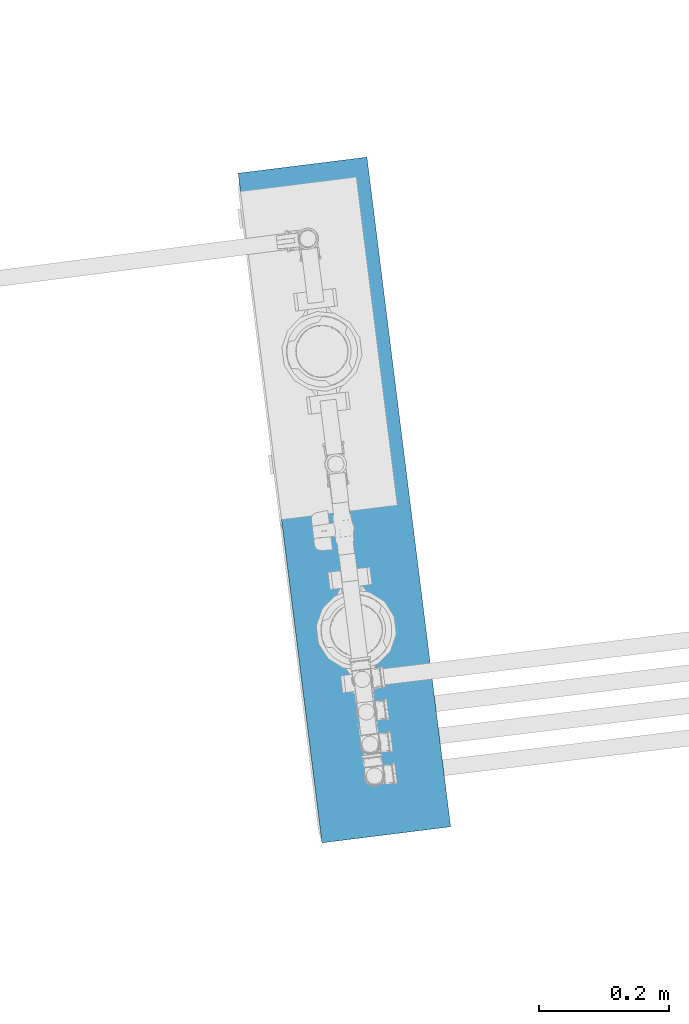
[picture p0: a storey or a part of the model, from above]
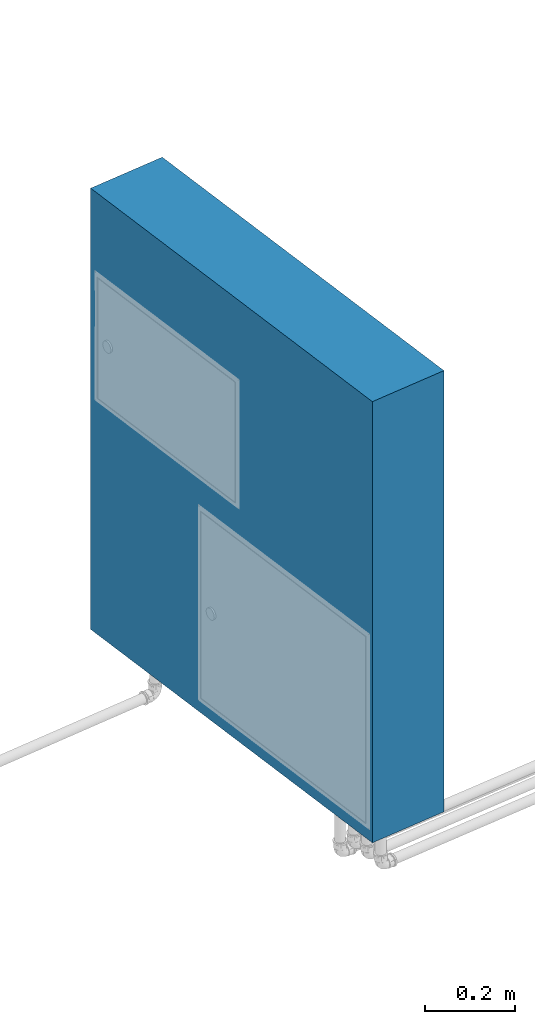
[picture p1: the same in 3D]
Properties of the parts of a building model (IFC2X3), part 1 of 2

# File
Description: ViewDefinition [CoordinationView_V2.0]
Time: 2023-04-20T11:42:16
Written by: The EXPRESS Data Manager Version 5.02.0100.07 : 28 Aug 2013
Made in: 22.0.2.392 - Exporter 22.0.2.392 - IU alternativa 22.0.2.392
Comment: STEP Physical File produced by: The EXPRESS Data Manager Version 5.02.0100.07 : 28 Aug 2013 * Module: EDMstepFileFactory/EDMstandAlone * Creation date: Thu Apr 20 11:42:16 2023 * Host: ESTACAO-11 * Database: D:\bruno.bestetti\AppData\Local\Temp\69208f3e-4a2d-469e-9d8b-66fd437b3669\e22d9549-68a2-4e91-86b9-adf0b3c94b80\ifc * Database version: 5507 * Database creation date: Thu Apr 20 11:41:43 2023 * Schema: IFC2X3 * Model: DataRepository.ifc * Model creation date: Thu Apr 20 11:41:44 2023 * Header model: DataRepository.ifc_HeaderModel * Header model creation date: Thu Apr 20 11:41:44 2023 * EDMuser: sdai-user * EDMgroup: sdai-group * License ID and type: 5605 : Permanent license. Expiry date: * EDMstepFileFactory options: 020000

# IfcProject
LongName: REVITALIZAÇÃO PRAÇA TEÓFILO SCHUTZ; Phase: EXECUTIVO

# IfcSite, Default
RefLatitude: 42, 24, 53, 508911; RefLongitude: -71, -15, -29, -58837; RefElevation: 0 cm

# IfcBuilding, HIDROSSANITÁRIO
LongName: HIDROSSANITÁRIO
Pset_BuildingCommon - NumberOfStoreys: 2

# IfcBuildingStorey: Nível:Nivel Rodrigo MEP (2)
In: HIDROSSANITÁRIO
Name | LongName | Elevation (cm)
TÉRREO-HID | TÉRREO-HID | -260
TERRENO | TERRENO | 0

# IfcBuildingElementProxy: Anel de Concreto para Fossa e Sumidouro_Rodrigo MEP:Anel de Concreto para Fossa e Sumidouro (6)
In: TÉRREO-HID
Type - Material: .CONCRETO
Type - Pset_ManufacturerTypeInformation - Manufacturer: -
Pset_BuildingElementProxyCommon - Reference: Anel de Concreto para Fossa e Sumidouro; sets with these values: 2
Name (Anel de Concreto para Fossa e Sumidouro_Rodrigo MEP:Anel de Concreto para Fossa e Sumidouro:...)
3760591
3761720
3761782
3761790
3761817
3761825

# IfcBuildingElementProxy: Tampa Fossa_Rodrigo MEP:Tampa Fossa (2)
In: TÉRREO-HID
Type - Material: .CONCRETO
Pset_BuildingElementProxyCommon - Reference: Tampa Fossa; sets with these values: 2
Name (Tampa Fossa_Rodrigo MEP:Tampa Fossa:...)
3757781
3757826

# IfcDistributionPort (947)
Description: Flow
Name | FlowDirection | Group
InPort_3621336 | SINK | Água Fria 1
2 x OutPort_3631671 | SOURCE | Água Fria 1
InPort_3621421 | SINK | Água Fria 1
OutPort_3621336 | SOURCE | Água Fria 1
InPort_3621553 | SINK | Água Fria 1
OutPort_3621421 | SOURCE | Água Fria 1
InPort_3622171 | SINK | Água Fria 1
OutPort_3622167 | SOURCE | Água Fria 1
InPort_3622167 | SINK | Água Fria 1
OutPort_3622169 | SOURCE | Água Fria 1
InPort_3622169 | SINK | Água Fria 1
OutPort_3622227 | SOURCE | Água Fria 1
InPort_3622173 | SINK | Água Fria 1
OutPort_3622171 | SOURCE | Água Fria 1
InPort_3622227 | SINK | Água Fria 1
Port_3622611 | SOURCEANDSINK | Esgoto Primário 1
InPort_3622611 | SOURCEANDSINK | Esgoto Primário 1
2 x OutPort_3706232 | SOURCEANDSINK | Esgoto Primário 1
2 x InPort_3622626 | SOURCEANDSINK | Esgoto Primário 1
OutPort_3647421 | SOURCEANDSINK | Esgoto Primário 1
InPort_3623081 | SOURCEANDSINK | Esgoto Primário 1
2 x OutPort_3623085 | SOURCEANDSINK | Esgoto Primário 1
Port_3623081 | SOURCEANDSINK | Esgoto Primário 1
2 x InPort_3623083 | SOURCEANDSINK | Esgoto Primário 1
OutPort_3623249 | SOURCEANDSINK | Esgoto Primário 1
2 x Port_3623087 | SOURCEANDSINK
InPort_3623102 | SOURCEANDSINK | Esgoto Primário 1
2 x OutPort_3623106 | SOURCEANDSINK | Esgoto Primário 1
Port_3623102 | SOURCEANDSINK | Esgoto Primário 1
2 x InPort_3623104 | SOURCEANDSINK | Esgoto Primário 1
OutPort_3623216 | SOURCEANDSINK | Esgoto Primário 1
2 x Port_3623108 | SOURCEANDSINK
InPort_3623121 | SOURCEANDSINK | Esgoto Primário 1
2 x OutPort_3623125 | SOURCEANDSINK | Esgoto Primário 1
Port_3623121 | SOURCEANDSINK | Esgoto Primário 1
2 x InPort_3623123 | SOURCEANDSINK | Esgoto Primário 1
OutPort_3623181 | SOURCEANDSINK | Esgoto Primário 1
2 x Port_3623127 | SOURCEANDSINK
2 x InPort_3623181 | SOURCEANDSINK | Esgoto Primário 1
OutPort_3624440 | SOURCEANDSINK | Esgoto Primário 1
2 x OutPort_3705811 | SOURCEANDSINK | Esgoto Primário 1
2 x Port_3623183 | SOURCEANDSINK
2 x InPort_3623216 | SOURCEANDSINK | Esgoto Primário 1
2 x OutPort_3624463 | SOURCEANDSINK | Esgoto Primário 1
2 x OutPort_3731357 | SOURCEANDSINK | Esgoto Primário 1
2 x Port_3623218 | SOURCEANDSINK
2 x InPort_3623249 | SOURCEANDSINK | Esgoto Primário 1
OutPort_3704790 | SOURCEANDSINK | Esgoto Primário 1
OutPort_3632646 | SOURCEANDSINK | Esgoto Primário 1
2 x Port_3623251 | SOURCEANDSINK
6 x Port_3623956 | SOURCE
InPort_3707539 | SINK | Esgoto Primário 1
OutPort_3623956 | SOURCE | Esgoto Primário 1
InPort_3623956 | SINK | Esgoto Primário 2
OutPort_3706054 | SOURCE | Esgoto Primário 2
InPort_3624235 | SINK | Esgoto Primário 1
OutPort_3707566 | SOURCE | Esgoto Primário 1
InPort_3624462 | SINK | Esgoto Primário 1
OutPort_3624235 | SOURCE | Esgoto Primário 1
InPort_3624440 | SOURCEANDSINK | Esgoto Primário 1
OutPort_3624462 | SOURCEANDSINK | Esgoto Primário 1
InPort_3624462 | SOURCEANDSINK | Esgoto Primário 1
2 x Port_3624466 | SOURCEANDSINK
InPort_3625453 | SINK | Esgoto Primário 2
OutPort_3625024 | SOURCE | Esgoto Primário 2
InPort_3625483 | SINK | Esgoto Primário 2
OutPort_3625453 | SOURCE | Esgoto Primário 2
InPort_3635714 | SINK | Esgoto Primário 2
OutPort_3625471 | SOURCE | Esgoto Primário 2
InPort_3625471 | SINK | Esgoto Primário 2
OutPort_3625483 | SOURCE | Esgoto Primário 2
2 x InPort_3635718 | SINK | Esgoto Primário 2
OutPort_3625487 | SOURCE | Esgoto Primário 2
InPort_3625487 | SINK | Esgoto Primário 2
OutPort_3635714 | SOURCE | Esgoto Primário 2
InPort_3625944 | SINK | Esgoto Primário 2
OutPort_3625943 | SOURCE | Esgoto Primário 2
InPort_3625948 | SINK | Esgoto Primário 2
OutPort_3625944 | SOURCE | Esgoto Primário 2
InPort_3625946 | SINK | Esgoto Primário 2
OutPort_3625948 | SOURCE | Esgoto Primário 2
InPort_3625952 | SINK | Esgoto Primário 2
OutPort_3625946 | SOURCE | Esgoto Primário 2
InPort_3625950 | SINK | Esgoto Primário 2
OutPort_3625952 | SOURCE | Esgoto Primário 2
InPort_3635676 | SINK | Esgoto Primário 2
OutPort_3625950 | SOURCE | Esgoto Primário 2
InPort_3628157 | SINK | Água Fria 4
2 x OutPort_3628572 | SOURCE | Água Fria 4
2 x Port_3628157 | SOURCE
2 x Port_3628157 | SINK
InPort_3723032 | SINK | Água Fria 1
2 x OutPort_3628157 | SOURCE | Água Fria 1
InPort_3630028 | SINK | Água Fria 1
InPort_3628157 | SINK | Água Fria 1
OutPort_3723612 | SOURCE | Água Fria 1
Port_3628158 | SOURCE
InPort_3628812 | SINK | Água Fria 4
InPort_3628572 | SINK | Água Fria 4
OutPort_3628157 | SOURCE | Água Fria 4
InPort_3628820 | SINK | Água Fria 4
OutPort_3628802 | SOURCE | Água Fria 4
InPort_3628802 | SINK | Água Fria 4
OutPort_3628812 | SOURCE | Água Fria 4
InPort_3628832 | SINK | Água Fria 4
OutPort_3628814 | SOURCE | Água Fria 4
InPort_3628814 | SINK | Água Fria 4
OutPort_3628820 | SOURCE | Água Fria 4
InPort_3628840 | SINK | Água Fria 4
OutPort_3628824 | SOURCE | Água Fria 4
InPort_3628824 | SINK | Água Fria 4
OutPort_3628832 | SOURCE | Água Fria 4
InPort_3648340 | SINK | Água Fria 4
OutPort_3628840 | SOURCE | Água Fria 4
InPort_3629752 | SINK | Água Fria 1
OutPort_3629689 | SOURCE | Água Fria 1
InPort_3629689 | SINK | Água Fria 1
2 x OutPort_3656299 | SOURCE | Água Fria 1
InPort_3630155 | SINK | Água Fria 1
OutPort_3629752 | SOURCE | Água Fria 1
InPort_3629826 | SINK | Água Fria 1
OutPort_3656307 | SOURCE | Água Fria 1
InPort_3629832 | SINK | Água Fria 1
OutPort_3629826 | SOURCE | Água Fria 1
InPort_3630368 | SINK | Água Fria 1
OutPort_3629832 | SOURCE | Água Fria 1
InPort_3629846 | SINK | Água Fria 1
OutPort_3656433 | SOURCE | Água Fria 1
InPort_3629852 | SINK | Água Fria 1
OutPort_3629846 | SOURCE | Água Fria 1
InPort_3630320 | SINK | Água Fria 1
OutPort_3629852 | SOURCE | Água Fria 1
InPort_3656427 | SINK | Água Fria 1
OutPort_3629868 | SOURCE | Água Fria 1
InPort_3629868 | SINK | Água Fria 1
OutPort_3632177 | SOURCE | Água Fria 1
InPort_3629874 | SINK | Água Fria 1
OutPort_3656428 | SOURCE | Água Fria 1
InPort_3630357 | SINK | Água Fria 1
OutPort_3629874 | SOURCE | Água Fria 1
InPort_3629916 | SINK | Água Fria 1
InPort_3656307 | SINK | Água Fria 1
OutPort_3629916 | SOURCE | Água Fria 1
InPort_3629988 | SINK | Água Fria 1
2 x OutPort_3656427 | SOURCE | Água Fria 1
InPort_3656433 | SINK | Água Fria 1
OutPort_3629988 | SOURCE | Água Fria 1
InPort_3657158 | SINK | Água Fria 1
OutPort_3630028 | SOURCE | Água Fria 1
InPort_3657128 | SINK | Água Fria 1
OutPort_3630072 | SOURCE | Água Fria 1
InPort_3630072 | SINK | Água Fria 1
2 x OutPort_3657158 | SOURCE | Água Fria 1
InPort_3630472 | SINK | Água Fria 1
OutPort_3630470 | SOURCE | Água Fria 1
InPort_3630470 | SINK | Água Fria 1
2 x OutPort_3631200 | SOURCE | Água Fria 1
InPort_3630476 | SINK | Água Fria 1
OutPort_3630472 | SOURCE | Água Fria 1
InPort_3630937 | SINK | Água Fria 1
OutPort_3656827 | SOURCE | Água Fria 1
InPort_3631019 | SINK | Água Fria 1
OutPort_3630937 | SOURCE | Água Fria 1
InPort_3631121 | SINK | Água Fria 1
OutPort_3631019 | SOURCE | Água Fria 1
InPort_3656764 | SINK | Água Fria 1
InPort_3631200 | SINK | Água Fria 1
OutPort_3631201 | SOURCE | Água Fria 1
InPort_3631201 | SINK | Água Fria 1
OutPort_3632300 | SOURCE | Água Fria 1
InPort_3632177 | SINK | Água Fria 1
OutPort_3631272 | SOURCE | Água Fria 1
InPort_3631272 | SINK | Água Fria 1
2 x OutPort_3656704 | SOURCE | Água Fria 1
InPort_3631287 | SINK | Água Fria 1
OutPort_3656568 | SOURCE | Água Fria 1
InPort_3656704 | SINK | Água Fria 1
OutPort_3631287 | SOURCE | Água Fria 1
InPort_3632149 | SINK | Água Fria 1
OutPort_3631337 | SOURCE | Água Fria 1
InPort_3631337 | SINK | Água Fria 1
2 x OutPort_3656640 | SOURCE | Água Fria 1
InPort_3656640 | SINK | Água Fria 1
OutPort_3631352 | SOURCE | Água Fria 1
InPort_3631352 | SINK | Água Fria 1
OutPort_3656571 | SOURCE | Água Fria 1
InPort_3631474 | SINK | Água Fria 1
2 x OutPort_3657128 | SOURCE | Água Fria 1
InPort_3656571 | SINK | Água Fria 1
OutPort_3631474 | SOURCE | Água Fria 1
InPort_3631671 | SINK | Água Fria 1
OutPort_3632028 | SOURCE | Água Fria 1
InPort_3632021 | SINK | Água Fria 1
OutPort_3631682 | SOURCE | Água Fria 1
InPort_3631682 | SINK | Água Fria 1
OutPort_3631703 | SOURCE | Água Fria 1
InPort_3631703 | SINK | Água Fria 1
OutPort_3631697 | SOURCE | Água Fria 1
InPort_3631697 | SINK | Água Fria 1
OutPort_3657137 | SOURCE | Água Fria 1
InPort_3632028 | SINK | Água Fria 1
OutPort_3632021 | SOURCE | Água Fria 1
InPort_3656460 | SINK | Água Fria 1
OutPort_3632149 | SOURCE | Água Fria 1
InPort_3632300 | SINK | Água Fria 1
OutPort_3632330 | SOURCE | Água Fria 1
InPort_3632330 | SINK | Água Fria 1
OutPort_3656670 | SOURCE | Água Fria 1
InPort_3633401 | SINK | Esgoto Primário 3
OutPort_3632400 | SOURCE | Esgoto Primário 3
Port_3632472 | SOURCEANDSINK | Esgoto Primário 1
InPort_3632472 | SOURCEANDSINK | Esgoto Primário 1
2 x OutPort_3705473 | SOURCEANDSINK | Esgoto Primário 1
InPort_3632646 | SOURCEANDSINK | Esgoto Primário 1
OutPort_3731356 | SOURCEANDSINK | Esgoto Primário 1
6 x Port_3633080 | SOURCE
InPort_3707350 | SINK | Esgoto Primário 1
OutPort_3633080 | SOURCE | Esgoto Primário 1
InPort_3633080 | SINK | Esgoto Primário 3
OutPort_3708016 | SOURCE | Esgoto Primário 3
InPort_3655015 | SINK | Esgoto Primário 3
OutPort_3633401 | SOURCE | Esgoto Primário 3
InPort_3633724 | SINK | Esgoto Primário 3
OutPort_3708036 | SOURCE | Esgoto Primário 3
InPort_3708065 | SINK | Esgoto Primário 3
OutPort_3633724 | SOURCE | Esgoto Primário 3
InPort_3708036 | SINK | Esgoto Primário 3
OutPort_3633733 | SOURCE | Esgoto Primário 3
InPort_3633733 | SINK | Esgoto Primário 3
OutPort_3655015 | SOURCE | Esgoto Primário 3
2 x InPort_3633823 | SOURCEANDSINK | Esgoto Primário 1
2 x OutPort_3705804 | SOURCEANDSINK | Esgoto Primário 1
OutPort_3635577 | SOURCE | Esgoto Primário 2
InPort_3635577 | SINK | Esgoto Primário 2
OutPort_3635676 | SOURCE | Esgoto Primário 2
InPort_3706054 | SINK | Esgoto Primário 2
OutPort_3635718 | SOURCE | Esgoto Primário 2
InPort_3637866 | SOURCEANDSINK | Gordura 1
OutPort_3637925 | SOURCEANDSINK | Gordura 1
Port_3637866 | SOURCEANDSINK | Gordura 1
InPort_3637925 | SOURCEANDSINK | Gordura 1
OutPort_3644001 | SOURCEANDSINK | Gordura 1
2 x Port_3637927 | SOURCEANDSINK
Port_3638030 | SOURCEANDSINK | Gordura 2
InPort_3638030 | SOURCEANDSINK | Gordura 2
OutPort_3638036 | SOURCEANDSINK | Gordura 2
InPort_3638036 | SOURCEANDSINK | Gordura 2
OutPort_3644162 | SOURCEANDSINK | Gordura 2
2 x Port_3638038 | SOURCEANDSINK
2 x Port_3638080 | SOURCEANDSINK | Esgoto Primário 7
2 x Port_3638102 | SOURCEANDSINK | Esgoto Primário 8
2 x Port_3638151 | SOURCEANDSINK | Esgoto Primário 9
2 x InPort_3708612 | SINK | Ventilação-ESG 3
OutPort_3638600 | SOURCE | Ventilação-ESG 3
InPort_3638600 | SINK | Ventilação-ESG 3
OutPort_3643844 | SOURCE | Ventilação-ESG 3
Port_3638873 | SOURCEANDSINK | Gordura 3
InPort_3638873 | SOURCEANDSINK | Gordura 3
OutPort_3638879 | SOURCEANDSINK | Gordura 3
InPort_3638879 | SOURCEANDSINK | Gordura 3
OutPort_3644209 | SOURCEANDSINK | Gordura 3
2 x Port_3638881 | SOURCEANDSINK
Port_3643488 | SOURCEANDSINK
InPort_3643999 | SOURCEANDSINK | Gordura 1
2 x OutPort_3644003 | SOURCEANDSINK | Gordura 1
Port_3643999 | SOURCEANDSINK | Gordura 1
InPort_3644001 | SOURCEANDSINK | Gordura 1
2 x Port_3644006 | SOURCEANDSINK
Port_3644160 | SOURCEANDSINK | Gordura 2
InPort_3644160 | SOURCEANDSINK | Gordura 2
2 x OutPort_3644164 | SOURCEANDSINK | Gordura 2
InPort_3644162 | SOURCEANDSINK | Gordura 2
2 x Port_3644166 | SOURCEANDSINK
2 x InPort_3644205 | SOURCEANDSINK | Gordura 3
2 x OutPort_3644211 | SOURCEANDSINK | Gordura 3
2 x OutPort_3644217 | SOURCEANDSINK | Gordura 3
Port_3644207 | SOURCEANDSINK | Gordura 3
InPort_3644207 | SOURCEANDSINK | Gordura 3
InPort_3644209 | SOURCEANDSINK | Gordura 3
2 x Port_3644213 | SOURCEANDSINK
2 x Port_3644220 | SOURCEANDSINK
InPort_3644762 | SINK | Água Fria 3
OutPort_3645447 | SOURCE | Água Fria 3
2 x InPort_3747857 | SINK | Água Fria 3
OutPort_3644762 | SOURCE | Água Fria 3
InPort_3644793 | SINK | Água Fria 3
OutPort_3644799 | SOURCE | Água Fria 3
InPort_3645447 | SINK | Água Fria 3
OutPort_3644793 | SOURCE | Água Fria 3
Port_3644799 | SOURCE | Água Fria 3
InPort_3645090 | SINK | Água Fria 6
OutPort_3645038 | SOURCE | Água Fria 6
InPort_3645038 | SINK | Água Fria 6
OutPort_3645042 | SOURCE | Água Fria 6
Port_3645042 | SOURCE | Água Fria 6
InPort_3645425 | SINK | Água Fria 6
OutPort_3645082 | SOURCE | Água Fria 6
InPort_3645082 | SINK | Água Fria 6
OutPort_3645090 | SOURCE | Água Fria 6
InPort_3713454 | SINK | Água Fria 6
OutPort_3645094 | SOURCE | Água Fria 6
InPort_3645094 | SINK | Água Fria 6
OutPort_3645425 | SOURCE | Água Fria 6
InPort_3645120 | SINK | Água Fria 8
OutPort_3645122 | SOURCE | Água Fria 8
InPort_3645126 | SINK | Água Fria 8
OutPort_3645120 | SOURCE | Água Fria 8
Port_3645122 | SOURCE | Água Fria 8
InPort_3645124 | SINK | Água Fria 8
OutPort_3645126 | SOURCE | Água Fria 8
InPort_3645130 | SINK | Água Fria 8
OutPort_3645124 | SOURCE | Água Fria 8
InPort_3713460 | SINK | Água Fria 8
OutPort_3645128 | SOURCE | Água Fria 8
InPort_3645128 | SINK | Água Fria 8
OutPort_3645130 | SOURCE | Água Fria 8
2 x InPort_3645422 | SOURCEANDSINK | AF 1
OutPort_3713738 | SOURCEANDSINK | AF 1
2 x OutPort_3713600 | SOURCEANDSINK | AF 1
InPort_3708268 | SINK | Ventilação-ESG 3
OutPort_3647016 | SOURCE | Ventilação-ESG 3
InPort_3647016 | SINK | Ventilação-ESG 3
OutPort_3647024 | SOURCE | Ventilação-ESG 3
InPort_3647024 | SINK | Ventilação-ESG 3
OutPort_3708613 | SOURCE | Ventilação-ESG 3
2 x Port_3647026 | SOURCEANDSINK
InPort_3647030 | SINK | Ventilação-ESG 3
OutPort_3708268 | SOURCE | Ventilação-ESG 3
3 x InPort_3708293 | SINK | Ventilação-ESG 3
OutPort_3647030 | SOURCE | Ventilação-ESG 3
InPort_3647421 | SOURCEANDSINK | Esgoto Primário 1
2 x OutPort_3704814 | SOURCEANDSINK | Esgoto Primário 1
2 x Port_3647425 | SOURCEANDSINK
InPort_3713685 | SINK | Água Fria 4
OutPort_3648340 | SOURCE | Água Fria 4
InPort_3648395 | SINK | Água Fria 4
OutPort_3648343 | SOURCE | Água Fria 4
InPort_3648343 | SINK | Água Fria 4
2 x OutPort_3713685 | SOURCE | Água Fria 4
InPort_3648495 | SINK | Água Fria 4
OutPort_3648393 | SOURCE | Água Fria 4
InPort_3648393 | SINK | Água Fria 4
OutPort_3648395 | SOURCE | Água Fria 4
InPort_3648461 | SINK | Água Fria 4
OutPort_3648495 | SOURCE | Água Fria 4
InPort_3648663 | SINK | AF 1
OutPort_3648586 | SOURCE | AF 1
InPort_3648586 | SINK | AF 1
OutPort_3713598 | SOURCE | AF 1
2 x InPort_3648667 | SINK | AF 1
OutPort_3648661 | SOURCE | AF 1
InPort_3648661 | SINK | AF 1
OutPort_3648663 | SOURCE | AF 1
OutPort_3648722 | SOURCE | AF 1
InPort_3648722 | SINK | Água Fria 4
OutPort_3648667 | SOURCE | Água Fria 4
InPort_3648798 | SINK | Água Fria 4
InPort_3713738 | SINK | AF 1
OutPort_3648798 | SOURCE | AF 1
Port_3654591 | SOURCEANDSINK | Esgoto Primário 1
InPort_3654591 | SOURCEANDSINK | Esgoto Primário 1
2 x OutPort_3654763 | SOURCEANDSINK | Esgoto Primário 1
2 x InPort_3654593 | SOURCEANDSINK | Esgoto Primário 1
OutPort_3704807 | SOURCEANDSINK | Esgoto Primário 1
2 x Port_3654765 | SOURCEANDSINK
2 x InPort_3654770 | SOURCEANDSINK | Esgoto Primário 1
OutPort_3705954 | SOURCEANDSINK | Esgoto Primário 1
2 x OutPort_3704813 | SOURCEANDSINK | Esgoto Primário 1
InPort_3654944 | SINK | Esgoto Primário 16
OutPort_3654927 | SOURCE | Esgoto Primário 16
InPort_3654976 | SINK | Esgoto Primário 16
OutPort_3654944 | SOURCE | Esgoto Primário 16
InPort_3654974 | SINK | Esgoto Primário 16
OutPort_3654976 | SOURCE | Esgoto Primário 16
InPort_3709365 | SINK | Esgoto Primário 16
OutPort_3654974 | SOURCE | Esgoto Primário 16
InPort_3656121 | SINK | Água Fria 1
2 x OutPort_3656126 | SOURCE | Água Fria 1
InPort_3656123 | SINK | Água Fria 1
OutPort_3656121 | SOURCE | Água Fria 1
InPort_3656125 | SINK | Água Fria 1
OutPort_3656123 | SOURCE | Água Fria 1
InPort_3656810 | SINK | Água Fria 1
InPort_3656126 | SINK | Água Fria 1
OutPort_3656127 | SOURCE | Água Fria 1
InPort_3656127 | SINK | Água Fria 1
OutPort_3656132 | SOURCE | Água Fria 1
InPort_3656132 | SINK | Água Fria 1
OutPort_3656137 | SOURCE | Água Fria 1
InPort_3656137 | SINK | Água Fria 1
OutPort_3656740 | SOURCE | Água Fria 1
InPort_3656299 | SINK | Água Fria 1
OutPort_3656460 | SOURCE | Água Fria 1
InPort_3656428 | SINK | Água Fria 1
InPort_3656568 | SINK | Água Fria 1
OutPort_3657129 | SOURCE | Água Fria 1
InPort_3656670 | SINK | Água Fria 1
OutPort_3656608 | SOURCE | Água Fria 1
InPort_3656608 | SINK | Água Fria 1
OutPort_3656668 | SOURCE | Água Fria 1
InPort_3656651 | SINK | Água Fria 1
InPort_3656668 | SINK | Água Fria 1
OutPort_3656651 | SOURCE | Água Fria 1
InPort_3656680 | SINK | Água Fria 1
OutPort_3656736 | SOURCE | Água Fria 1
InPort_3656740 | SINK | Água Fria 1
OutPort_3656680 | SOURCE | Água Fria 1
InPort_3656717 | SINK | Água Fria 1
InPort_3656736 | SINK | Água Fria 1
OutPort_3656717 | SOURCE | Água Fria 1
InPort_3656747 | SINK | Água Fria 1
OutPort_3656906 | SOURCE | Água Fria 1
InPort_3657037 | SINK | Água Fria 1
OutPort_3656764 | SOURCE | Água Fria 1
InPort_3656827 | SINK | Água Fria 1
OutPort_3656810 | SOURCE | Água Fria 1
InPort_3656906 | SINK | Água Fria 1
OutPort_3656889 | SOURCE | Água Fria 1
InPort_3656889 | SINK | Água Fria 1
OutPort_3656916 | SOURCE | Água Fria 1
InPort_3656910 | SINK | Água Fria 1
OutPort_3657037 | SOURCE | Água Fria 1
InPort_3656916 | SINK | Água Fria 1
OutPort_3656910 | SOURCE | Água Fria 1
InPort_3657129 | SINK | Água Fria 1
InPort_3657137 | SINK | Água Fria 1
OutPort_3657159 | SOURCE | Água Fria 1
InPort_3657159 | SINK | Água Fria 1
InPort_3707780 | SINK | Esgoto Primário 1
OutPort_3704736 | SOURCE | Esgoto Primário 1
6 x Port_3704736 | SOURCE
InPort_3704736 | SINK | Esgoto Primário 16
OutPort_3709222 | SOURCE | Esgoto Primário 16
InPort_3704790 | SOURCEANDSINK | Esgoto Primário 1
InPort_3704807 | SOURCEANDSINK | Esgoto Primário 1
2 x OutPort_3705955 | SOURCEANDSINK | Esgoto Primário 1
InPort_3704813 | SOURCEANDSINK | Esgoto Primário 1
2 x Port_3704817 | SOURCEANDSINK
InPort_3705362 | SINK | Esgoto Primário 1
OutPort_3708322 | SOURCE | Esgoto Primário 1
InPort_3705954 | SINK | Esgoto Primário 1
OutPort_3705362 | SOURCE | Esgoto Primário 1
InPort_3731356 | SINK | Esgoto Primário 1
OutPort_3705419 | SOURCE | Esgoto Primário 1
InPort_3705419 | SINK | Esgoto Primário 1
OutPort_3731349 | SOURCE | Esgoto Primário 1
2 x Port_3705477 | SOURCEANDSINK
2 x InPort_3705484 | SOURCEANDSINK | Esgoto Primário 1
2 x OutPort_3705810 | SOURCEANDSINK | Esgoto Primário 1
InPort_3705697 | SINK | Ventilação-ESG 3
OutPort_3709076 | SOURCE | Ventilação-ESG 3
InPort_3709069 | SINK | Ventilação-ESG 3
OutPort_3705697 | SOURCE | Ventilação-ESG 3
InPort_3708717 | SINK | Ventilação-ESG 3
OutPort_3705716 | SOURCE | Ventilação-ESG 3
InPort_3705716 | SINK | Ventilação-ESG 3
OutPort_3709069 | SOURCE | Ventilação-ESG 3
Port_3705791 | SOURCEANDSINK | Esgoto Primário 1
InPort_3705791 | SOURCEANDSINK | Esgoto Primário 1
InPort_3705810 | SOURCEANDSINK | Esgoto Primário 1
2 x Port_3705814 | SOURCEANDSINK
InPort_3705954 | SOURCEANDSINK | Esgoto Primário 1
2 x Port_3705958 | SOURCEANDSINK
2 x Port_3706248 | SOURCEANDSINK
InPort_3708247 | SINK | Esgoto Primário 1
OutPort_3707350 | SOURCE | Esgoto Primário 1
2 x Port_3707418 | SOURCEANDSINK
2 x Port_3707440 | SOURCEANDSINK
InPort_3709048 | SINK | Esgoto Primário 1
OutPort_3707539 | SOURCE | Esgoto Primário 1
InPort_3707566 | SINK | Esgoto Primário 1
OutPort_3709049 | SOURCE | Esgoto Primário 1
2 x Port_3707568 | SOURCEANDSINK
InPort_3707797 | SINK | Esgoto Primário 1
OutPort_3707780 | SOURCE | Esgoto Primário 1
InPort_3708323 | SINK | Esgoto Primário 1
OutPort_3707797 | SOURCE | Esgoto Primário 1
2 x Port_3707811 | SOURCEANDSINK
InPort_3708016 | SINK | Esgoto Primário 3
OutPort_3708065 | SOURCE | Esgoto Primário 3
InPort_3709363 | SINK | Esgoto Primário 16
OutPort_3708127 | SOURCE | Esgoto Primário 16
InPort_3708127 | SINK | Esgoto Primário 16
OutPort_3709365 | SOURCE | Esgoto Primário 16
InPort_3708245 | SINK | Ventilação-ESG 3
OutPort_3708247 | SOURCE | Ventilação-ESG 3
OutPort_3708245 | SOURCE | Ventilação-ESG 3
InPort_3708248 | SINK | Esgoto Primário 1
OutPort_3708247 | SOURCE | Esgoto Primário 1
InPort_3731349 | SINK | Esgoto Primário 1
OutPort_3708248 | SOURCE | Esgoto Primário 1
2 x Port_3708252 | SOURCEANDSINK
2 x Port_3708271 | SOURCEANDSINK
OutPort_3708307 | SOURCE | Ventilação-ESG 3
2 x Port_3708296 | SOURCEANDSINK
InPort_3708307 | SINK | Ventilação-ESG 3
OutPort_3708465 | SOURCE | Ventilação-ESG 3
2 x InPort_3708322 | SINK | Esgoto Primário 1
OutPort_3708320 | SOURCE | Esgoto Primário 1
InPort_3708465 | SINK | Ventilação-ESG 3
OutPort_3708320 | SOURCE | Ventilação-ESG 3
OutPort_3708323 | SOURCE | Esgoto Primário 1
2 x Port_3708327 | SOURCEANDSINK
InPort_3708604 | SINK | Ventilação-ESG 3
OutPort_3708721 | SOURCE | Ventilação-ESG 3
OutPort_3708604 | SOURCE | Ventilação-ESG 3
InPort_3708613 | SINK | Ventilação-ESG 3
OutPort_3708612 | SOURCE | Ventilação-ESG 3
2 x Port_3708616 | SOURCEANDSINK
InPort_3708618 | SINK | Ventilação-ESG 3
OutPort_3708717 | SOURCE | Ventilação-ESG 3
InPort_3708721 | SINK | Ventilação-ESG 3
OutPort_3708618 | SOURCE | Ventilação-ESG 3
2 x Port_3708723 | SOURCEANDSINK
2 x Port_3708734 | SOURCEANDSINK
InPort_3709076 | SINK | Ventilação-ESG 3
OutPort_3709046 | SOURCE | Ventilação-ESG 3
InPort_3709046 | SINK | Ventilação-ESG 3
OutPort_3709048 | SOURCE | Ventilação-ESG 3
InPort_3709049 | SINK | Esgoto Primário 1
OutPort_3709048 | SOURCE | Esgoto Primário 1
2 x Port_3709053 | SOURCEANDSINK
2 x Port_3709072 | SOURCEANDSINK
InPort_3709222 | SINK | Esgoto Primário 16
OutPort_3709363 | SOURCE | Esgoto Primário 16
2 x InPort_3709927 | SOURCEANDSINK | AF 1
OutPort_3710419 | SOURCEANDSINK | AF 1
OutPort_3710365 | SOURCEANDSINK | AF 1
2 x InPort_3710125 | SOURCEANDSINK | AF 1
OutPort_3711963 | SOURCEANDSINK | AF 1
2 x OutPort_3716735 | SOURCEANDSINK | AF 1
Port_3710139 | SOURCEANDSINK | AF 1
InPort_3710139 | SOURCEANDSINK | AF 1
InPort_3710365 | SOURCEANDSINK | AF 1
OutPort_3710383 | SOURCEANDSINK | AF 1
2 x InPort_3710375 | SOURCEANDSINK | AF 1
OutPort_3711683 | SOURCEANDSINK | AF 1
OutPort_3711643 | SOURCEANDSINK | AF 1
InPort_3710383 | SOURCEANDSINK | AF 1
2 x OutPort_3711668 | SOURCEANDSINK | AF 1
InPort_3710419 | SOURCEANDSINK | AF 1
OutPort_3710435 | SOURCEANDSINK | AF 1
InPort_3710435 | SOURCEANDSINK | AF 1
2 x OutPort_3712017 | SOURCEANDSINK | AF 1
InPort_3710490 | SINK | AF 1
OutPort_3712304 | SOURCE | AF 1
InPort_3712685 | SINK | AF 1
OutPort_3710490 | SOURCE | AF 1
InPort_3712638 | SINK | AF 1
OutPort_3711396 | SOURCE | AF 1
InPort_3711396 | SINK | AF 1
OutPort_3712334 | SOURCE | AF 1
InPort_3711462 | SINK | AF 1
OutPort_3711576 | SOURCE | AF 1
InPort_3712589 | SINK | AF 1
OutPort_3711462 | SOURCE | AF 1
InPort_3711506 | SINK | AF 1
OutPort_3711667 | SOURCE | AF 1
InPort_3712302 | SINK | AF 1
OutPort_3711506 | SOURCE | AF 1
InPort_3711548 | SINK | AF 1
OutPort_3711643 | SOURCE | AF 1
InPort_3712332 | SINK | AF 1
OutPort_3711548 | SOURCE | AF 1
InPort_3711576 | SINK | AF 1
OutPort_3712367 | SOURCE | AF 1
InPort_3711643 | SOURCEANDSINK | AF 1
OutPort_3711644 | SOURCEANDSINK | AF 1
InPort_3711644 | SOURCEANDSINK | AF 1
OutPort_3711667 | SOURCEANDSINK | AF 1
InPort_3711667 | SOURCEANDSINK | AF 1
InPort_3711683 | SOURCEANDSINK | AF 1
OutPort_3711694 | SOURCEANDSINK | AF 1
InPort_3712369 | SINK | AF 1
OutPort_3711683 | SOURCE | AF 1
InPort_3711694 | SOURCEANDSINK | AF 1
2 x OutPort_3713502 | SOURCEANDSINK | AF 1
InPort_3711963 | SOURCEANDSINK | AF 1
InPort_3712304 | SINK | AF 1
OutPort_3712302 | SOURCE | AF 1
InPort_3712334 | SINK | AF 1
OutPort_3712332 | SOURCE | AF 1
InPort_3712367 | SINK | AF 1
OutPort_3712369 | SOURCE | AF 1
InPort_3712607 | SINK | AF 1
OutPort_3712589 | SOURCE | AF 1
InPort_3712599 | SINK | AF 1
OutPort_3712607 | SOURCE | AF 1
InPort_3713284 | SINK | AF 1
OutPort_3712599 | SOURCE | AF 1
InPort_3712654 | SINK | AF 1
OutPort_3712638 | SOURCE | AF 1
InPort_3712646 | SINK | AF 1
OutPort_3712654 | SOURCE | AF 1
InPort_3713261 | SINK | AF 1
OutPort_3712646 | SOURCE | AF 1
InPort_3712701 | SINK | AF 1
OutPort_3712685 | SOURCE | AF 1
InPort_3747836 | SINK | AF 1
OutPort_3712693 | SOURCE | AF 1
InPort_3712693 | SINK | AF 1
OutPort_3712701 | SOURCE | AF 1
2 x InPort_3713113 | SINK | AF 1
OutPort_3713284 | SOURCE | AF 1
OutPort_3713460 | SOURCE | AF 1
2 x InPort_3713154 | SINK | AF 1
OutPort_3713454 | SOURCE | AF 1
OutPort_3713261 | SOURCE | AF 1
OutPort_3713192 | SOURCE | Água Fria 3
InPort_3713192 | SINK | AF 1
OutPort_3747836 | SOURCE | AF 1
2 x InPort_3713494 | SOURCEANDSINK | AF 1
2 x OutPort_3713514 | SOURCEANDSINK | AF 1
2 x InPort_3713506 | SOURCEANDSINK | AF 1
InPort_3713598 | SINK | AF 1
OutPort_3723843 | SOURCE | AF 1
InPort_3713739 | SINK | AF 1
OutPort_3713738 | SOURCE | AF 1
2 x InPort_3723842 | SINK | AF 1
OutPort_3713739 | SOURCE | AF 1
2 x Port_3716076 | SOURCEANDSINK | Esgoto Primário 4
2 x Port_3716108 | SOURCEANDSINK | Esgoto Primário 5
2 x Port_3716134 | SOURCEANDSINK | Esgoto Primário 6
2 x Port_3716157 | SOURCEANDSINK | Esgoto Primário 10
2 x Port_3716200 | SOURCEANDSINK | Esgoto Primário 11
2 x Port_3716255 | SOURCEANDSINK | Esgoto Primário 12
2 x Port_3716327 | SOURCEANDSINK | Esgoto Primário 13
2 x Port_3717081 | SOURCEANDSINK | Drenagem 3
2 x Port_3717124 | SOURCEANDSINK | Drenagem 4
2 x Port_3717274 | SOURCEANDSINK | Águas Pluviais 1
2 x Port_3717319 | SOURCEANDSINK | Águas Pluviais 5
2 x Port_3717344 | SOURCEANDSINK | Águas Pluviais 6
2 x Port_3717476 | SOURCEANDSINK | Drenagem 12
2 x Port_3717705 | SOURCEANDSINK | Drenagem 6
2 x Port_3717763 | SOURCEANDSINK | Drenagem 7
2 x Port_3717939 | SOURCEANDSINK | Drenagem 16
2 x Port_3717997 | SOURCEANDSINK | Drenagem 15
2 x Port_3718083 | SOURCEANDSINK | Drenagem 14
2 x Port_3718330 | SOURCEANDSINK | Drenagem 17
2 x Port_3718717 | SOURCEANDSINK | Drenagem 18
2 x Port_3718749 | SOURCEANDSINK | Águas Pluviais 4
2 x Port_3718777 | SOURCEANDSINK | Águas Pluviais 7
2 x Port_3718875 | SOURCEANDSINK | Águas Pluviais 8
2 x Port_3718898 | SOURCEANDSINK | Águas Pluviais 9
2 x Port_3719265 | SOURCEANDSINK | Drenagem 13
2 x Port_3719337 | SOURCEANDSINK | Águas Pluviais 3
2 x Port_3720543 | SOURCEANDSINK | Águas Pluviais 2
2 x InPort_3723633 | SINK | Água Fria 1
OutPort_3723032 | SOURCE | Água Fria 1
InPort_3723119 | SINK | Água Fria 1
OutPort_3749834 | SOURCE | Água Fria 1
InPort_3723586 | SINK | Água Fria 1
OutPort_3723119 | SOURCE | Água Fria 1
InPort_3723593 | SINK | Água Fria 1
OutPort_3723508 | SOURCE | Água Fria 1
InPort_3723508 | SINK | Água Fria 1
OutPort_3723586 | SOURCE | Água Fria 1
InPort_3723634 | SINK | Água Fria 1
OutPort_3723593 | SOURCE | Água Fria 1
InPort_3723612 | SINK | Água Fria 1
OutPort_3723637 | SOURCE | Água Fria 1
InPort_3723620 | SINK | Água Fria 1
OutPort_3723633 | SOURCE | Água Fria 1
InPort_3723637 | SINK | Água Fria 1
OutPort_3723620 | SOURCE | Água Fria 1
OutPort_3723634 | SOURCE | Água Fria 1
OutPort_3723828 | SOURCE | AF 1
InPort_3723828 | SINK | Água Fria 2
OutPort_3723899 | SOURCE | Água Fria 2
InPort_3723843 | SINK | AF 1
OutPort_3723842 | SOURCE | AF 1
InPort_3723899 | SINK | Água Fria 2
OutPort_3723897 | SOURCE | Água Fria 2
InPort_3723897 | SINK | Água Fria 2
OutPort_3723903 | SOURCE | Água Fria 2
Port_3723903 | SOURCE | Água Fria 2
2 x Port_3731352 | SOURCEANDSINK
InPort_3731356 | SOURCEANDSINK | Esgoto Primário 1
2 x Port_3731362 | SOURCEANDSINK
2 x InPort_3733850 | SOURCEANDSINK | Águas Pluviais 15
2 x OutPort_3786813 | SOURCEANDSINK | Águas Pluviais 15
2 x OutPort_3788636 | SOURCEANDSINK | Águas Pluviais 15
InPort_3733852 | SOURCEANDSINK | Águas Pluviais 15
Port_3733852 | SOURCEANDSINK | Águas Pluviais 15
InPort_3749822 | SINK | Água Fria 1
OutPort_3749844 | SOURCE | Água Fria 1
InPort_3749834 | SINK | Água Fria 1
OutPort_3749822 | SOURCE | Água Fria 1
Port_3749838 | SOURCE | Água Fria 1
InPort_3749844 | SINK | Água Fria 1
OutPort_3749838 | SOURCE | Água Fria 1
2 x Port_3777648 | SOURCEANDSINK | Águas Pluviais 16
2 x Port_3777893 | SOURCEANDSINK | Águas Pluviais 17
2 x Port_3777992 | SOURCEANDSINK | Águas Pluviais 18
2 x Port_3779134 | SOURCEANDSINK | Drenagem 5
2 x Port_3779149 | SOURCEANDSINK | Drenagem 9
2 x Port_3779476 | SOURCEANDSINK | Drenagem 1
2 x Port_3779489 | SOURCEANDSINK | Drenagem 2
2 x Port_3779559 | SOURCEANDSINK | Drenagem 11
2 x Port_3779626 | SOURCEANDSINK | Drenagem 19
2 x Port_3781268 | SOURCEANDSINK | Águas Pluviais 19
2 x Port_3781398 | SOURCEANDSINK | Drenagem 10
2 x Port_3781491 | SOURCEANDSINK | Águas Pluviais 20
2 x Port_3781812 | SOURCEANDSINK | Águas Pluviais 21
2 x Port_3781858 | SOURCEANDSINK | Águas Pluviais 22
2 x Port_3786815 | SOURCEANDSINK
2 x InPort_3788624 | SOURCEANDSINK | Águas Pluviais 15
2 x OutPort_3788650 | SOURCEANDSINK | Águas Pluviais 15
InPort_3788642 | SOURCEANDSINK | Águas Pluviais 15
Port_3788642 | SOURCEANDSINK | Águas Pluviais 15
2 x Port_3788668 | SOURCEANDSINK
2 x Port_3788688 | SOURCEANDSINK
2 x InPort_3788895 | SOURCEANDSINK | Águas Pluviais 23
2 x OutPort_3788905 | SOURCEANDSINK | Águas Pluviais 23
2 x OutPort_3789779 | SOURCEANDSINK | Águas Pluviais 23
Port_3788897 | SOURCEANDSINK | Águas Pluviais 23
InPort_3788897 | SOURCEANDSINK | Águas Pluviais 23
2 x InPort_3788903 | SOURCEANDSINK | Águas Pluviais 23
2 x OutPort_3788909 | SOURCEANDSINK | Águas Pluviais 23
InPort_3788907 | SOURCEANDSINK | Águas Pluviais 23
Port_3788907 | SOURCEANDSINK | Águas Pluviais 23
2 x Port_3788911 | SOURCEANDSINK
2 x Port_3788913 | SOURCEANDSINK
2 x Port_3789781 | SOURCEANDSINK
2 x InPort_3789901 | SOURCEANDSINK | Águas Pluviais 10
2 x OutPort_3789911 | SOURCEANDSINK | Águas Pluviais 10
OutPort_3790635 | SOURCEANDSINK | Águas Pluviais 10
2 x InPort_3789909 | SOURCEANDSINK | Águas Pluviais 10
2 x OutPort_3789915 | SOURCEANDSINK | Águas Pluviais 10
InPort_3789913 | SOURCEANDSINK | Águas Pluviais 10
Port_3789913 | SOURCEANDSINK | Águas Pluviais 10
2 x Port_3789917 | SOURCEANDSINK
2 x Port_3789919 | SOURCEANDSINK
2 x InPort_3789962 | SOURCEANDSINK | Águas Pluviais 12
2 x OutPort_3791097 | SOURCEANDSINK | Águas Pluviais 12
2 x OutPort_3789968 | SOURCEANDSINK | Águas Pluviais 12
2 x InPort_3789966 | SOURCEANDSINK | Águas Pluviais 12
2 x OutPort_3789972 | SOURCEANDSINK | Águas Pluviais 12
InPort_3789970 | SOURCEANDSINK | Águas Pluviais 12
Port_3789970 | SOURCEANDSINK | Águas Pluviais 12
2 x Port_3789974 | SOURCEANDSINK
2 x Port_3789976 | SOURCEANDSINK
Port_3790635 | SOURCEANDSINK | Águas Pluviais 10
2 x Port_3790637 | SOURCEANDSINK
2 x InPort_3790805 | SOURCEANDSINK | Águas Pluviais 12
2 x OutPort_3791163 | SOURCEANDSINK | Águas Pluviais 12
InPort_3790819 | SOURCEANDSINK | Águas Pluviais 12
Port_3790819 | SOURCEANDSINK | Águas Pluviais 12
2 x Port_3791099 | SOURCEANDSINK
2 x Port_3791165 | SOURCEANDSINK

# IfcFlowController: Adaptador com Anel - Agua Fria_Soldavel - MEP - Tigre:Standard (2)
In: TÉRREO-HID
Type - Material: PVC Marrom
Type - Pset_ManufacturerTypeInformation - Manufacturer: © Tigre S/A
Pset_DistributionFlowElementCommon - Reference: Standard; sets with these values: 2
Name (Adaptador com Anel - Agua Fria_Soldavel - MEP - Tigre:Standard:...)
3628160
3723375

# IfcFlowController: Adaptador com Registro - Agua Fria_Soldavel - MEP - Tigre:Standard, Adaptador com Registro - Agua Fria_Soldavel - MEP - Tigre:Standard:3723291
In: TÉRREO-HID
Type - Material: PVC Marrom, Phenolic Resin
Type - Pset_ManufacturerTypeInformation - Manufacturer: © Tigre S/A
Material: Phenolic Resin, PVC Marrom
Pset_DistributionFlowElementCommon - Reference: Standard; sets with these values: 2

# IfcFlowController: Adaptador com Registro - Agua Fria_Soldavel - MEP - Tigre:Standard, Adaptador com Registro - Agua Fria_Soldavel - MEP - Tigre:Standard:3628159
In: TÉRREO-HID
Type - Material: Phenolic Resin, PVC Marrom
Type - Pset_ManufacturerTypeInformation - Manufacturer: © Tigre S/A
Pset_DistributionFlowElementCommon - Reference: Standard; sets with these values: 2

# IfcFlowController: Hidrometro:25x25mm (4)
In: TÉRREO-HID
Type - Material: PVC, Flexible, Plastic, Opaque Black, Laminate, Navy
Pset_DistributionFlowElementCommon - Reference: 25x25mm; sets with these values: 2
Group: AF 1
Name (Hidrometro:25x25mm:...)
3709927
3710490
3711396
3711462

# IfcFlowController: Registro Esfera com Borboleta - Agua Fria - MEP - Tigre:3/4" (4)
In: TÉRREO-HID
Type - Material: <Unnamed>
Type - Pset_ManufacturerTypeInformation - Manufacturer: © Tigre S/A
Pset_DistributionFlowElementCommon - Reference: 3/4"; sets with these values: 2
Group: AF 1
Name (Registro Esfera com Borboleta - Agua Fria - MEP - Tigre:3/4":...)
3711963
3712302
3712332
3712367

# IfcFlowController: Registro de Gaveta:b. RG_Ø3/4" (25mm) (5)
In: TÉRREO-HID
Type - Material: Branco - Docol, BRONZE, .BRANCO
Type - Pset_ManufacturerTypeInformation - Manufacturer: Docol
Material: Branco - Docol, BRONZE; Group: Água Fria 1
Pset_DistributionFlowElementCommon - Reference: b. RG_Ø3/4" (25mm); sets with these values: 2
Name (Registro de Gaveta:b. RG_Ø3/4" (25mm):...)
3632021
3632149
3632177
3632300
3656132

# IfcFlowFitting: Joelho 45_90 - Agua Fria_Soldavel - MEP - Tigre:Standard (47)
Type - Material: PVC Marrom
Type - Pset_ManufacturerTypeInformation - Manufacturer: © Tigre S/A
Pset_DistributionFlowElementCommon - Reference: Standard; sets with these values: 2
Name (Joelho 45_90 - Agua Fria_Soldavel - MEP - Tigre:Standard:...) | In | Group
3622169 | TÉRREO-HID | Água Fria 1
3628812 | TÉRREO-HID | Água Fria 4
3628820 | TÉRREO-HID | Água Fria 4
3628832 | TÉRREO-HID | Água Fria 4
3628840 | TÉRREO-HID | Água Fria 4
3631703 | TÉRREO-HID | Água Fria 1
3645090 | TÉRREO-HID | Água Fria 6
3645126 | TÉRREO-HID | Água Fria 8
3645130 | TÉRREO-HID | Água Fria 8
3645425 | TÉRREO-HID | Água Fria 6
3645447 | TÉRREO-HID | Água Fria 3
3648395 | TÉRREO-HID | Água Fria 4
3648663 | TÉRREO-HID | AF 1
3656307 | TÉRREO-HID | Água Fria 1
3656433 | TÉRREO-HID | Água Fria 1
3656568 | TÉRREO-HID | Água Fria 1
3656571 | TÉRREO-HID | Água Fria 1
3656668 | TERRENO | Água Fria 1
3656670 | TÉRREO-HID | Água Fria 1
3656736 | TERRENO | Água Fria 1
3656740 | TÉRREO-HID | Água Fria 1
3656827 | TÉRREO-HID | Água Fria 1
3656916 | TÉRREO-HID | Água Fria 1
3657037 | TÉRREO-HID | Água Fria 1
3657137 | TÉRREO-HID | Água Fria 1
3710383 | TÉRREO-HID | AF 1
3710435 | TÉRREO-HID | AF 1
3712607 | TÉRREO-HID | AF 1
3712654 | TÉRREO-HID | AF 1
3712701 | TÉRREO-HID | AF 1
3713261 | TÉRREO-HID | AF 1
3713284 | TÉRREO-HID | AF 1
3713454 | TÉRREO-HID | Água Fria 6; AF 1
3713460 | TÉRREO-HID | Água Fria 8; AF 1
3713502 | TÉRREO-HID | AF 1
3713514 | TÉRREO-HID | AF 1
3713598 | TÉRREO-HID | AF 1
3713600 | TÉRREO-HID | AF 1
3716735 | TÉRREO-HID | AF 1
3723586 | TERRENO | Água Fria 1
3723593 | TÉRREO-HID | Água Fria 1
3723637 | TÉRREO-HID | Água Fria 1
3723899 | TÉRREO-HID | Água Fria 2
3747836 | TÉRREO-HID | AF 1
3747857 | TÉRREO-HID | Água Fria 3
3749834 | TERRENO | Água Fria 1
3749844 | TERRENO | Água Fria 1

# IfcFlowFitting: Joelho 45_90 - Serie Normal - Esgoto - MEP - Tigre:Standard (50)
Type - Material: PVC Branco
Type - Pset_ManufacturerTypeInformation - Manufacturer: © Tigre S/A
Pset_DistributionFlowElementCommon - Reference: Standard; sets with these values: 2
Name (Joelho 45_90 - Serie Normal - Esgoto - MEP - Tigre:Standard:...) | In | Group
3623085 | TÉRREO-HID | Esgoto Primário 1
3623106 | TÉRREO-HID | Esgoto Primário 1
3623125 | TÉRREO-HID | Esgoto Primário 1
3625483 | TÉRREO-HID | Esgoto Primário 2
3625948 | TÉRREO-HID | Esgoto Primário 2
3625952 | TÉRREO-HID | Esgoto Primário 2
3635676 | TÉRREO-HID | Esgoto Primário 2
3635714 | TÉRREO-HID | Esgoto Primário 2
3637925 | TÉRREO-HID | Gordura 1
3638036 | TÉRREO-HID | Gordura 2
3638879 | TÉRREO-HID | Gordura 3
3644003 | TÉRREO-HID | Gordura 1
3644164 | TÉRREO-HID | Gordura 2
3644211 | TÉRREO-HID | Gordura 3
3644217 | TÉRREO-HID | Gordura 3
3647024 | TÉRREO-HID | Ventilação-ESG 3
3647421 | TÉRREO-HID | Esgoto Primário 1
3654763 | TÉRREO-HID | Esgoto Primário 1
3654976 | TÉRREO-HID | Esgoto Primário 16
3655015 | TÉRREO-HID | Esgoto Primário 3
3704807 | TÉRREO-HID | Esgoto Primário 1
3705473 | TÉRREO-HID | Esgoto Primário 1
3705804 | TÉRREO-HID | Esgoto Primário 1
3706232 | TÉRREO-HID | Esgoto Primário 1
3707566 | TÉRREO-HID | Esgoto Primário 1
3707797 | TÉRREO-HID | Esgoto Primário 1
3708036 | TÉRREO-HID | Esgoto Primário 3
3708065 | TÉRREO-HID | Esgoto Primário 3
3708268 | TÉRREO-HID | Ventilação-ESG 3
3708465 | TÉRREO-HID | Ventilação-ESG 3
3708717 | TÉRREO-HID | Ventilação-ESG 3
3708721 | TÉRREO-HID | Ventilação-ESG 3
3709069 | TÉRREO-HID | Ventilação-ESG 3
3709076 | TÉRREO-HID | Ventilação-ESG 3
3709363 | TÉRREO-HID | Esgoto Primário 16
3709365 | TÉRREO-HID | Esgoto Primário 16
3731349 | TERRENO | Esgoto Primário 1
3786813 | TÉRREO-HID | Águas Pluviais 15
3788636 | TÉRREO-HID | Águas Pluviais 15
3788650 | TÉRREO-HID | Águas Pluviais 15
3788905 | TÉRREO-HID | Águas Pluviais 23
3788909 | TÉRREO-HID | Águas Pluviais 23
3789779 | TÉRREO-HID | Águas Pluviais 23
3789911 | TÉRREO-HID | Águas Pluviais 10
3789915 | TÉRREO-HID | Águas Pluviais 10
3789968 | TÉRREO-HID | Águas Pluviais 12
3789972 | TÉRREO-HID | Águas Pluviais 12
3790635 | TÉRREO-HID | Águas Pluviais 10
3791097 | TÉRREO-HID | Águas Pluviais 12
3791163 | TERRENO | Águas Pluviais 12

# IfcFlowFitting: Joelho 90 com Bucha de Latao - Agua Fria_Soldavel - MEP - Tigre:Joelho 90 Redução com Bucha de latão - Água Fria_Soldável - Tigre (16)
Type - Material: PVC Azul
Type - Pset_ManufacturerTypeInformation - Manufacturer: © Tigre S/A
Pset_DistributionFlowElementCommon - Reference: Joelho 90 Redução com Bucha de latão - Água Fria_Soldável - Tigre; sets with these values: 2
Name (Joelho 90 com Bucha de Latao - Agua Fria_Soldavel - MEP - Tigre:Joelho 90 Redução com Bucha de latão - Água Fria_Soldável - Tigre:...) | In | Group
3621421 | TÉRREO-HID | Água Fria 1
3622171 | TÉRREO-HID | Água Fria 1
3629752 | TÉRREO-HID | Água Fria 1
3629832 | TÉRREO-HID | Água Fria 1
3629852 | TÉRREO-HID | Água Fria 1
3629874 | TÉRREO-HID | Água Fria 1
3630472 | TÉRREO-HID | Água Fria 1
3631019 | TÉRREO-HID | Água Fria 1
3644799 | TÉRREO-HID | Água Fria 3
3645042 | TÉRREO-HID | Água Fria 6
3645122 | TÉRREO-HID | Água Fria 8
3648495 | TÉRREO-HID | Água Fria 4
3648667 | TÉRREO-HID | Água Fria 4; AF 1
3656123 | TÉRREO-HID | Água Fria 1
3656906 | TERRENO | Água Fria 1
3723903 | TÉRREO-HID | Água Fria 2

# IfcFlowFitting: Juncao - Serie Normal - Esgoto - MEP - Tigre:Standard (10)
In: TÉRREO-HID
Type - Material: PVC Branco
Type - Pset_ManufacturerTypeInformation - Manufacturer: © Tigre S/A
Pset_DistributionFlowElementCommon - Reference: Standard; sets with these values: 2
Name (Juncao - Serie Normal - Esgoto - MEP - Tigre:Standard:...) | Group
3623181 | Esgoto Primário 1
3623216 | Esgoto Primário 1
3623249 | Esgoto Primário 1
3624462 | Esgoto Primário 1
3635718 | Esgoto Primário 2
3704813 | Esgoto Primário 1
3705810 | Esgoto Primário 1
3705954 | Esgoto Primário 1
3708612 | Ventilação-ESG 3
3731356 | Esgoto Primário 1

# IfcFlowFitting: Luva Simples para Conexão - Serie Normal - Esgoto - MEP - Tigre:Standard (50)
Type - Material: PVC Branco
Type - Pset_ManufacturerTypeInformation - Manufacturer: © Tigre S/A
Pset_DistributionFlowElementCommon - Reference: Standard; sets with these values: 2
Name (Luva Simples para Conexão - Serie Normal - Esgoto - MEP - Tigre:Standard:...) | In
3623087 | TÉRREO-HID
3623108 | TÉRREO-HID
3623127 | TÉRREO-HID
3623183 | TÉRREO-HID
3623218 | TÉRREO-HID
3623251 | TÉRREO-HID
3624466 | TÉRREO-HID
3637927 | TÉRREO-HID
3638038 | TÉRREO-HID
3638881 | TÉRREO-HID
3644006 | TÉRREO-HID
3644166 | TÉRREO-HID
3644213 | TÉRREO-HID
3644220 | TÉRREO-HID
3647026 | TÉRREO-HID
3647425 | TÉRREO-HID
3654765 | TÉRREO-HID
3704817 | TÉRREO-HID
3705477 | TÉRREO-HID
3705814 | TÉRREO-HID
3705958 | TÉRREO-HID
3706248 | TÉRREO-HID
3707418 | TÉRREO-HID
3707440 | TÉRREO-HID
3707568 | TÉRREO-HID
3707811 | TÉRREO-HID
3708252 | TÉRREO-HID
3708271 | TÉRREO-HID
3708296 | TÉRREO-HID
3708327 | TÉRREO-HID
3708616 | TÉRREO-HID
3708723 | TÉRREO-HID
3708734 | TÉRREO-HID
3709053 | TÉRREO-HID
3709072 | TÉRREO-HID
3731352 | TERRENO
3731362 | TÉRREO-HID
3786815 | TÉRREO-HID
3788668 | TÉRREO-HID
3788688 | TÉRREO-HID
3788911 | TÉRREO-HID
3788913 | TÉRREO-HID
3789781 | TÉRREO-HID
3789917 | TÉRREO-HID
3789919 | TÉRREO-HID
3789974 | TÉRREO-HID
3789976 | TÉRREO-HID
3790637 | TÉRREO-HID
3791099 | TÉRREO-HID
3791165 | TERRENO

# IfcFlowFitting: PVC Marrom Soldável_Adaptador Curto com Bolsa e Rosca Aninhado:Adaptador (10)
In: TÉRREO-HID
Type - Material: PVC Marrom
Type - Pset_ManufacturerTypeInformation - Manufacturer: Tigre
Pset_DistributionFlowElementCommon - Reference: Adaptador; sets with these values: 2
Name (PVC Marrom Soldável_Adaptador Curto com Bolsa e Rosca Aninhado:Adaptador:...)
3632022
3632023
3632150
3632151
3632178
3632179
3632301
3632302
3656133
3656134

# IfcFlowFitting: Te - Serie Normal - Esgoto - MEP - Tigre:Standard (4)
In: TÉRREO-HID
Type - Material: PVC Branco
Type - Pset_ManufacturerTypeInformation - Manufacturer: © Tigre S/A
Pset_DistributionFlowElementCommon - Reference: Standard; sets with these values: 2
Name (Te - Serie Normal - Esgoto - MEP - Tigre:Standard:...) | Group
3708247 | Esgoto Primário 1; Ventilação-ESG 3
3708293 | Ventilação-ESG 3
3708322 | Esgoto Primário 1
3709048 | Esgoto Primário 1; Ventilação-ESG 3

# IfcFlowFitting: Te_Reducao - Agua Fria_Soldavel - MEP - Tigre:Standard (16)
Type - Material: PVC Marrom
Type - Pset_ManufacturerTypeInformation - Manufacturer: © Tigre S/A
Pset_DistributionFlowElementCommon - Reference: Standard; sets with these values: 2
Name (Te_Reducao - Agua Fria_Soldavel - MEP - Tigre:Standard:...) | In | Group
3631200 | TÉRREO-HID | Água Fria 1
3631671 | TÉRREO-HID | Água Fria 1
3656126 | TÉRREO-HID | Água Fria 1
3656299 | TÉRREO-HID | Água Fria 1
3656427 | TÉRREO-HID | Água Fria 1
3656640 | TÉRREO-HID | Água Fria 1
3656704 | TÉRREO-HID | Água Fria 1
3657128 | TERRENO | Água Fria 1
3657158 | TÉRREO-HID | Água Fria 1
3711643 | TÉRREO-HID | AF 1
3711667 | TÉRREO-HID | AF 1
3711683 | TÉRREO-HID | AF 1
3713685 | TÉRREO-HID | Água Fria 4
3713738 | TÉRREO-HID | AF 1
3723633 | TÉRREO-HID | Água Fria 1
3723842 | TÉRREO-HID | AF 1

# IfcFlowFitting: Terminal de Ventilacao - Serie Normal - Esgoto - MEP - Tigre:Standard, Terminal de Ventilacao - Serie Normal - Esgoto - MEP - Tigre:Standard:3643844
In: TÉRREO-HID
Type - Material: PVC Branco
Type - Pset_ManufacturerTypeInformation - Manufacturer: © Tigre S/A
Pset_DistributionFlowElementCommon - Reference: Standard; sets with these values: 2
Group: Ventilação-ESG 3

# IfcFlowSegment: Tipos de tubos:Tubo - Esgoto - Série Normal (112)
Type - Pset_ManufacturerTypeInformation - Manufacturer: Tigre S.A.
Pset_DistributionFlowElementCommon - Reference: Tubo - Esgoto - Série Normal; sets with these values: 2
Pset_FlowSegmentDuctSegment - sets with these values: 2
Name (Tipos de tubos:Tubo - Esgoto - Série Normal:...) | In | Length (cm) | Group
3622611 | TÉRREO-HID | 18.434 | Esgoto Primário 1
3622626 | TÉRREO-HID | 36.7693 | Esgoto Primário 1
3623081 | TÉRREO-HID | 19.0535 | Esgoto Primário 1
3623083 | TÉRREO-HID | 27.0995 | Esgoto Primário 1
3623102 | TÉRREO-HID | 19.2617 | Esgoto Primário 1
3623104 | TÉRREO-HID | 27.1629 | Esgoto Primário 1
3623121 | TÉRREO-HID | 20.0259 | Esgoto Primário 1
3623123 | TÉRREO-HID | 27.1549 | Esgoto Primário 1
3624235 | TÉRREO-HID | 34.9351 | Esgoto Primário 1
3624440 | TÉRREO-HID | 48.0554 | Esgoto Primário 1
3624463 | TÉRREO-HID | 14.1934 | Esgoto Primário 1
3625453 | TÉRREO-HID | 1.09067 | Esgoto Primário 2
3625471 | TÉRREO-HID | 76.8845 | Esgoto Primário 2
3625487 | TÉRREO-HID | 18.4737 | Esgoto Primário 2
3625944 | TÉRREO-HID | 1.24704 | Esgoto Primário 2
3625946 | TÉRREO-HID | 76.0101 | Esgoto Primário 2
3625950 | TÉRREO-HID | 22.5964 | Esgoto Primário 2
3632472 | TÉRREO-HID | 19.2846 | Esgoto Primário 1
3632646 | TÉRREO-HID | 23.7616 | Esgoto Primário 1
3633401 | TÉRREO-HID | 1.49471 | Esgoto Primário 3
3633724 | TÉRREO-HID | 23.2379 | Esgoto Primário 3
3633733 | TÉRREO-HID | 76.4797 | Esgoto Primário 3
3633823 | TÉRREO-HID | 30.0687 | Esgoto Primário 1
3635577 | TÉRREO-HID | 53.9481 | Esgoto Primário 2
3637866 | TÉRREO-HID | 4.88 | Gordura 1
3638030 | TÉRREO-HID | 4.88 | Gordura 2
3638080 | TÉRREO-HID | 274.014 | Esgoto Primário 7
3638102 | TÉRREO-HID | 180 | Esgoto Primário 8
3638151 | TÉRREO-HID | 280.014 | Esgoto Primário 9
3638600 | TÉRREO-HID | 306.147 | Ventilação-ESG 3
3638873 | TÉRREO-HID | 4.88 | Gordura 3
3643999 | TÉRREO-HID | 47.9315 | Gordura 1
3644001 | TÉRREO-HID | 68.8115 | Gordura 1
3644160 | TÉRREO-HID | 44.9411 | Gordura 2
3644162 | TÉRREO-HID | 68.8115 | Gordura 2
3644205 | TÉRREO-HID | 39.6599 | Gordura 3
3644207 | TÉRREO-HID | 339.303 | Gordura 3
3644209 | TÉRREO-HID | 68.8115 | Gordura 3
3647016 | TÉRREO-HID | 41.8274 | Ventilação-ESG 3
3647030 | TÉRREO-HID | 34.07 | Ventilação-ESG 3
3654591 | TÉRREO-HID | 17.7826 | Esgoto Primário 1
3654593 | TÉRREO-HID | 21.5379 | Esgoto Primário 1
3654770 | TÉRREO-HID | 14.6018 | Esgoto Primário 1
3654944 | TÉRREO-HID | 1.5 | Esgoto Primário 16
3654974 | TÉRREO-HID | 75.9714 | Esgoto Primário 16
3704790 | TÉRREO-HID | 33.5117 | Esgoto Primário 1
3704814 | TÉRREO-HID | 27.4732 | Esgoto Primário 1
3705362 | TÉRREO-HID | 81.8901 | Esgoto Primário 1
3705419 | TÉRREO-HID | 65.063 | Esgoto Primário 1
3705484 | TÉRREO-HID | 81.2845 | Esgoto Primário 1
3705697 | TÉRREO-HID | 48.5002 | Ventilação-ESG 3
3705716 | TÉRREO-HID | 157.44 | Ventilação-ESG 3
3705791 | TÉRREO-HID | 99.2994 | Esgoto Primário 1
3705811 | TÉRREO-HID | 15.7328 | Esgoto Primário 1
3705955 | TÉRREO-HID | 62.637 | Esgoto Primário 1
3706054 | TÉRREO-HID | 22.8449 | Esgoto Primário 2
3707350 | TERRENO | 43.6327 | Esgoto Primário 1
3707539 | TERRENO | 95.5089 | Esgoto Primário 1
3707780 | TERRENO | 26.3947 | Esgoto Primário 1
3708016 | TÉRREO-HID | 22.4258 | Esgoto Primário 3
3708127 | TÉRREO-HID | 23.5731 | Esgoto Primário 16
3708245 | TÉRREO-HID | 6.17779 | Ventilação-ESG 3
3708248 | TERRENO | 59.5935 | Esgoto Primário 1
3708307 | TÉRREO-HID | 58.1411 | Ventilação-ESG 3
3708320 | TÉRREO-HID | 1.64308 | Esgoto Primário 1; Ventilação-ESG 3
3708323 | TÉRREO-HID | 20.4374 | Esgoto Primário 1
3708604 | TÉRREO-HID | 13.3362 | Ventilação-ESG 3
3708613 | TÉRREO-HID | 107.651 | Ventilação-ESG 3
3708618 | TÉRREO-HID | 97.3349 | Ventilação-ESG 3
3709046 | TÉRREO-HID | 1.57216 | Ventilação-ESG 3
3709049 | TERRENO | 56.8517 | Esgoto Primário 1
3709222 | TÉRREO-HID | 11.8773 | Esgoto Primário 16
3716076 | TÉRREO-HID | 192.01 | Esgoto Primário 4
3716108 | TÉRREO-HID | 992.15 | Esgoto Primário 5
3716134 | TÉRREO-HID | 736.037 | Esgoto Primário 6
3716157 | TÉRREO-HID | 173.5 | Esgoto Primário 10
3716200 | TÉRREO-HID | 70 | Esgoto Primário 11
3716255 | TÉRREO-HID | 102.005 | Esgoto Primário 12
3716327 | TÉRREO-HID | 92.0046 | Esgoto Primário 13
3717274 | TERRENO | 1250.01 | Águas Pluviais 1
3717319 | TERRENO | 808 | Águas Pluviais 5
3717344 | TERRENO | 420.011 | Águas Pluviais 6
3718749 | TERRENO | 900 | Águas Pluviais 4
3718777 | TERRENO | 1230 | Águas Pluviais 7
3718875 | TERRENO | 930 | Águas Pluviais 8
3718898 | TERRENO | 237.859 | Águas Pluviais 9
3719337 | TERRENO | 1502.46 | Águas Pluviais 3
3720543 | TERRENO | 1194.04 | Águas Pluviais 2
3731357 | TÉRREO-HID | 38.5482 | Esgoto Primário 1
3733850 | TÉRREO-HID | 488.252 | Águas Pluviais 15
3733852 | TÉRREO-HID | 840.363 | Águas Pluviais 15
3777648 | TERRENO | 807.634 | Águas Pluviais 16
3777893 | TERRENO | 420.011 | Águas Pluviais 17
3777992 | TERRENO | 1206.04 | Águas Pluviais 18
3781268 | TERRENO | 1217.26 | Águas Pluviais 19
3781491 | TERRENO | 1223.97 | Águas Pluviais 20
3781812 | TERRENO | 930 | Águas Pluviais 21
3781858 | TERRENO | 242.012 | Águas Pluviais 22
3788624 | TÉRREO-HID | 170.2 | Águas Pluviais 15
3788642 | TÉRREO-HID | 8.1 | Águas Pluviais 15
3788895 | TÉRREO-HID | 479.122 | Águas Pluviais 23
3788897 | TÉRREO-HID | 202.152 | Águas Pluviais 23
3788903 | TÉRREO-HID | 170.202 | Águas Pluviais 23
3788907 | TÉRREO-HID | 8.1 | Águas Pluviais 23
3789901 | TÉRREO-HID | 109.637 | Águas Pluviais 10
3789909 | TÉRREO-HID | 170.2 | Águas Pluviais 10
3789913 | TÉRREO-HID | 8.1 | Águas Pluviais 10
3789962 | TÉRREO-HID | 448.751 | Águas Pluviais 12
3789966 | TÉRREO-HID | 170.202 | Águas Pluviais 12
3789970 | TÉRREO-HID | 9.1 | Águas Pluviais 12
3790805 | TERRENO | 218.737 | Águas Pluviais 12
3790819 | TERRENO | 1118.66 | Águas Pluviais 12

# IfcFlowSegment: Tipos de tubos:Tubo Marrom - Água Fria - Soldável (95)
Type - Pset_ManufacturerTypeInformation - Manufacturer: Tigre S.A.
Pset_DistributionFlowElementCommon - Reference: Tubo Marrom - Água Fria - Soldável; sets with these values: 2
Pset_FlowSegmentDuctSegment - sets with these values: 2
Name (Tipos de tubos:Tubo Marrom - Água Fria - Soldável:...) | In | Length (cm) | Group
3621336 | TÉRREO-HID | 16.78 | Água Fria 1
3622167 | TÉRREO-HID | 16.83 | Água Fria 1
3622227 | TÉRREO-HID | 57.01 | Água Fria 1
3628572 | TÉRREO-HID | 4.96 | Água Fria 4
3628802 | TÉRREO-HID | 61.0314 | Água Fria 4
3628814 | TÉRREO-HID | 134.92 | Água Fria 4
3628824 | TÉRREO-HID | 278.309 | Água Fria 4
3629689 | TÉRREO-HID | 6.78 | Água Fria 1
3629826 | TÉRREO-HID | 6.83 | Água Fria 1
3629846 | TÉRREO-HID | 6.83 | Água Fria 1
3629868 | TÉRREO-HID | 146.41 | Água Fria 1
3629916 | TÉRREO-HID | 94.2567 | Água Fria 1
3629988 | TÉRREO-HID | 94.2328 | Água Fria 1
3630028 | TÉRREO-HID | 17.7525 | Água Fria 1
3630072 | TERRENO | 75.2515 | Água Fria 1
3630470 | TÉRREO-HID | 46.78 | Água Fria 1
3630937 | TÉRREO-HID | 130.785 | Água Fria 1
3631201 | TÉRREO-HID | 106.41 | Água Fria 1
3631272 | TÉRREO-HID | 93.9403 | Água Fria 1
3631287 | TÉRREO-HID | 55.2401 | Água Fria 1
3631337 | TÉRREO-HID | 93.9389 | Água Fria 1
3631352 | TÉRREO-HID | 55.2225 | Água Fria 1
3631474 | TERRENO | 234.154 | Água Fria 1
3631682 | TÉRREO-HID | 93.8503 | Água Fria 1
3631697 | TÉRREO-HID | 58.0434 | Água Fria 1
3632028 | TÉRREO-HID | 96.41 | Água Fria 1
3632330 | TÉRREO-HID | 93.849 | Água Fria 1
3644762 | TÉRREO-HID | 430.871 | Água Fria 3
3644793 | TÉRREO-HID | 71.83 | Água Fria 3
3645038 | TÉRREO-HID | 71.83 | Água Fria 6
3645082 | TÉRREO-HID | 14.2708 | Água Fria 6
3645094 | TÉRREO-HID | 392.524 | Água Fria 6
3645120 | TÉRREO-HID | 71.83 | Água Fria 8
3645124 | TÉRREO-HID | 14.4042 | Água Fria 8
3645128 | TÉRREO-HID | 392.292 | Água Fria 8
3645422 | TÉRREO-HID | 536.607 | AF 1
3648340 | TÉRREO-HID | 8.92665 | Água Fria 4
3648343 | TÉRREO-HID | 161.87 | Água Fria 4
3648393 | TÉRREO-HID | 46.83 | Água Fria 4
3648586 | TÉRREO-HID | 240.958 | AF 1
3648661 | TÉRREO-HID | 46.83 | AF 1
3648798 | TÉRREO-HID | 273.712 | Água Fria 4; AF 1
3656121 | TÉRREO-HID | 36.78 | Água Fria 1
3656127 | TÉRREO-HID | 116.41 | Água Fria 1
3656137 | TÉRREO-HID | 93.8489 | Água Fria 1
3656428 | TÉRREO-HID | 6.78 | Água Fria 1
3656460 | TÉRREO-HID | 146.41 | Água Fria 1
3656608 | TERRENO | 26.8724 | Água Fria 1
3656651 | TERRENO | 6.30523 | Água Fria 1
3656680 | TERRENO | 27.2071 | Água Fria 1
3656717 | TERRENO | 6.13153 | Água Fria 1
3656764 | TÉRREO-HID | 78.3177 | Água Fria 1
3656810 | TERRENO | 205.948 | Água Fria 1
3656889 | TÉRREO-HID | 6.83 | Água Fria 1
3656910 | TÉRREO-HID | 146.114 | Água Fria 1
3657129 | TERRENO | 51.3459 | Água Fria 1
3657159 | TERRENO | 108.569 | Água Fria 1
3710125 | TÉRREO-HID | 85.405 | AF 1
3710139 | TÉRREO-HID | 508.54 | AF 1
3710365 | TÉRREO-HID | 8.39059 | AF 1
3710375 | TÉRREO-HID | 11.82 | AF 1
3710419 | TÉRREO-HID | 8.39075 | AF 1
3711506 | TÉRREO-HID | 4.55716 | AF 1
3711548 | TÉRREO-HID | 4.55726 | AF 1
3711576 | TÉRREO-HID | 4.18929 | AF 1
3711644 | TÉRREO-HID | 11.82 | AF 1
3711668 | TÉRREO-HID | 36.8353 | AF 1
3711694 | TÉRREO-HID | 4.96 | AF 1
3712017 | TÉRREO-HID | 4.521 | AF 1
3712304 | TÉRREO-HID | 4.18929 | AF 1
3712334 | TÉRREO-HID | 4.18939 | AF 1
3712369 | TÉRREO-HID | 4.55716 | AF 1
3712589 | TÉRREO-HID | 3.627 | AF 1
3712599 | TÉRREO-HID | 27.9547 | AF 1
3712638 | TÉRREO-HID | 8.62696 | AF 1
3712646 | TÉRREO-HID | 42.9547 | AF 1
3712685 | TÉRREO-HID | 13.578 | AF 1
3712693 | TÉRREO-HID | 57.9547 | AF 1
3713113 | TÉRREO-HID | 3207.38 | AF 1
3713154 | TÉRREO-HID | 2176.81 | AF 1
3713192 | TÉRREO-HID | 1707.5 | Água Fria 3; AF 1
3713494 | TÉRREO-HID | 30.3507 | AF 1
3713506 | TÉRREO-HID | 24.8647 | AF 1
3713739 | TÉRREO-HID | 1456.36 | AF 1
3723032 | TÉRREO-HID | 14.6349 | Água Fria 1
3723119 | TERRENO | 198.1 | Água Fria 1
3723508 | TÉRREO-HID | 18.4886 | Água Fria 1
3723612 | TÉRREO-HID | 12.6924 | Água Fria 1
3723620 | TÉRREO-HID | 44.1214 | Água Fria 1
3723634 | TÉRREO-HID | 28.8624 | Água Fria 1
3723828 | TÉRREO-HID | 1566.74 | Água Fria 2; AF 1
3723843 | TÉRREO-HID | 2469.66 | AF 1
3723897 | TÉRREO-HID | 46.93 | Água Fria 2
3749822 | TERRENO | 248.95 | Água Fria 1
3749838 | TERRENO | 10.0334 | Água Fria 1

# IfcFlowSegment: Tubulação flexível redonda:PEAD Corrugado (18)
In: TERRENO
Type - PredefinedType: FLEXIBLESEGMENT
Type - Pset_ManufacturerTypeInformation - Manufacturer: Tigre S.A.
Pset_DistributionFlowElementCommon - Reference: PEAD Corrugado; sets with these values: 2
Name (Tubulação flexível redonda:PEAD Corrugado:...) | Group
3717081 | Drenagem 3
3717124 | Drenagem 4
3717476 | Drenagem 12
3717705 | Drenagem 6
3717763 | Drenagem 7
3717939 | Drenagem 16
3717997 | Drenagem 15
3718083 | Drenagem 14
3718330 | Drenagem 17
3718717 | Drenagem 18
3719265 | Drenagem 13
3779134 | Drenagem 5
3779149 | Drenagem 9
3779476 | Drenagem 1
3779489 | Drenagem 2
3779559 | Drenagem 11
3779626 | Drenagem 19
3781398 | Drenagem 10

# IfcFlowTerminal: CE HS SNT CAIXA DE INSPEÇÃO:INSPEÇÃO 60cm, CE HS SNT CAIXA DE INSPEÇÃO:INSPEÇÃO 60cm:3643488
In: TÉRREO-HID
Type - Material: <Unnamed> (4)
Pset_DistributionFlowElementCommon - Reference: INSPEÇÃO 60cm; sets with these values: 2

# IfcFlowTerminal: CE HS-HID Abrigo hidrômetros:32x50x20, CE HS-HID Abrigo hidrômetros:32x50x20:3721887
In: TÉRREO-HID
Type - Material: Padrão
Material: Padrão, Vidro
Pset_DistributionFlowElementCommon - Reference: 32x50x20; sets with these values: 2

# IfcFlowTerminal: CE HS-HID Abrigo hidrômetros:60x60x20, CE HS-HID Abrigo hidrômetros:60x60x20:3721914
In: TÉRREO-HID
Type - Material: Padrão
Material: Padrão, Vidro
Pset_DistributionFlowElementCommon - Reference: 60x60x20; sets with these values: 2

# IfcFlowTerminal: CE HS-SNT CALHA:CE HS-SNT CALHA (2)
In: TERRENO
Type - Material: <Unnamed>
Pset_DistributionFlowElementCommon - Reference: CE HS-SNT CALHA; sets with these values: 2
Name (CE HS-SNT CALHA:CE HS-SNT CALHA:...)
3787696
3788055

# IfcFlowTerminal: Caixa D_Agua_Completa_2014 - Agua Fria - MEP -Tigre:Caixa com Tampa - 500 L, Caixa D_Agua_Completa_2014 - Agua Fria - MEP -Tigre:Caixa com Tampa - 500 L:3628157
In: TÉRREO-HID
Type - Material: PVC Marrom, PEMD Azul
Type - Pset_ManufacturerTypeInformation - Manufacturer: © Tigre S/A
Material: PEMD Azul; Group: Água Fria 1; Água Fria 4
Pset_DistributionFlowElementCommon - Reference: Caixa com Tampa - 500 L; sets with these values: 2

# IfcFlowTerminal: Caixa Sifonada Montada_150x150x50_7 Entradas Completa - Caixas e Ralos - Esgoto - MEP - Tigre:Grelha e porta grelha quadrados brancos - DN 150 x 150 x 50 (3)
In: TÉRREO-HID
Type - Material: Tigre - Caixas e Ralos_PVC Branco
Type - Pset_ManufacturerTypeInformation - Manufacturer: © Tigre S/A
Pset_DistributionFlowElementCommon - Reference: Grelha e porta grelha quadrados brancos - DN 150 x 150 x 50; sets with these values: 2
Name (Caixa Sifonada Montada_150x150x50_7 Entradas Completa - Caixas e Ralos - Esgoto - MEP - Tigre:Grelha e porta grelha quadrados brancos - DN 150 x 150 x 50:...) | Group
3623956 | Esgoto Primário 1; Esgoto Primário 2
3633080 | Esgoto Primário 1; Esgoto Primário 3
3704736 | Esgoto Primário 1; Esgoto Primário 16

# IfcFlowTerminal: Caixa de Inspeção/Gordura:Alvenaria (17)
In: TÉRREO-HID
Type - Material: <Unnamed>, Concrete, Sand/Cement Screed, Brick, Common, Grey
Pset_DistributionFlowElementCommon - Reference: Alvenaria; sets with these values: 2
Name (Caixa de Inspeção/Gordura:Alvenaria:...)
3626134
3636876
3636975
3637533
3637644
3637658
3652020
3652667
3715930
3716493
3716542
3716800
3716994
3717665
3718839
3719147
3780738

# IfcFlowTerminal: Pontos de Consumo :BACIA SANITARIA CAIXA ACOPLADA (6)
In: TÉRREO-HID
Type - Material: .ID PONTOS DE CONSUMO (3), <Unnamed>
Pset_DistributionFlowElementCommon - Reference: BACIA SANITARIA CAIXA ACOPLADA; sets with these values: 2
Group: Água Fria 1
Name (Pontos de Consumo :BACIA SANITARIA CAIXA ACOPLADA:...) | Material
3630155
3630320 | .ID PONTOS DE CONSUMO, <Unnamed>
3630357 | .ID PONTOS DE CONSUMO, <Unnamed>
3630368 | .ID PONTOS DE CONSUMO, <Unnamed>
3630476 | .ID PONTOS DE CONSUMO, <Unnamed>
3656125 | .ID PONTOS DE CONSUMO, <Unnamed>

# IfcFlowTerminal: Pontos de Consumo :LAVATÓRIO (4)
Type - Material: .ID PONTOS DE CONSUMO (2), <Unnamed>
Pset_DistributionFlowElementCommon - Reference: LAVATÓRIO; sets with these values: 2
Group: Água Fria 1
Name (Pontos de Consumo :LAVATÓRIO:...) | In | Material
3621553 | TÉRREO-HID
3622173 | TÉRREO-HID | .ID PONTOS DE CONSUMO, <Unnamed>
3631121 | TÉRREO-HID | .ID PONTOS DE CONSUMO, <Unnamed>
3656747 | TERRENO | .ID PONTOS DE CONSUMO, <Unnamed>

# IfcFlowTerminal: Pontos de Consumo :TORNEIRA JARDIM (2)
In: TÉRREO-HID
Type - Material: .ID PONTOS DE CONSUMO (2), <Unnamed>
Pset_DistributionFlowElementCommon - Reference: TORNEIRA JARDIM; sets with these values: 2
Name (Pontos de Consumo :TORNEIRA JARDIM:...) | Group
3648461 | Água Fria 4
3648722 | Água Fria 4; AF 1 | Material: .ID PONTOS DE CONSUMO, <Unnamed>

# IfcFlowTerminal: Prolongamento para Caixa Sifonada - Caixas e Ralos - Esgoto - MEP - Tigre:150 x 150 mm (3)
In: TÉRREO-HID
Type - Material: Tigre - Caixas e Ralos_PVC Branco
Type - Pset_ManufacturerTypeInformation - Manufacturer: © Tigre S/A
Pset_DistributionFlowElementCommon - Reference: 150 x 150 mm; sets with these values: 2
Name (Prolongamento para Caixa Sifonada - Caixas e Ralos - Esgoto - MEP - Tigre:150 x 150 mm:...)
3624290
3633082
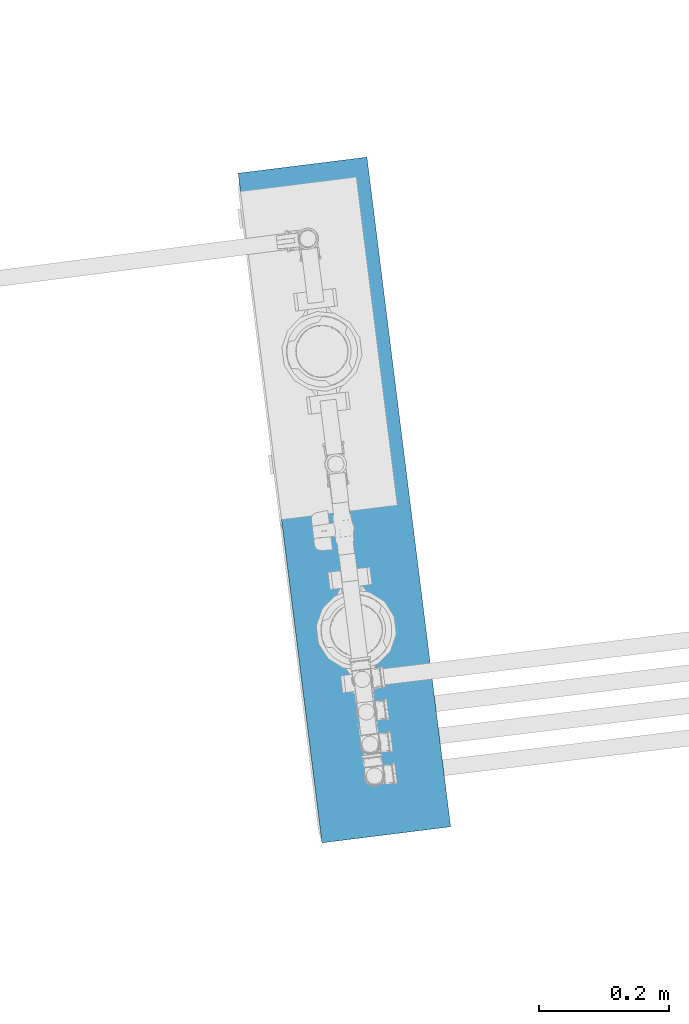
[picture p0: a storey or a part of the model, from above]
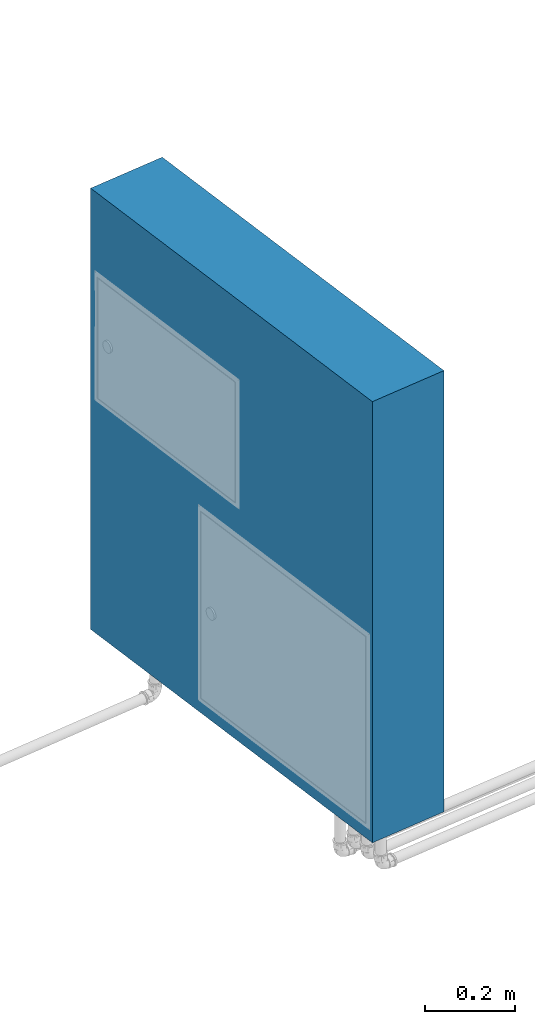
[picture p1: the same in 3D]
Properties of the parts of a building model (IFC2X3), part 2 of 2

# IfcFlowTerminal: Prolongamento para Caixa Sifonada - Caixas e Ralos - Esgoto - MEP - Tigre:150 x 150 mm (3)
Name (Prolongamento para Caixa Sifonada - Caixas e Ralos - Esgoto - MEP - Tigre:150 x 150 mm:...)
3704737

# IfcFlowTerminal: Sifao para lavatorio - DocolBasicos:Lavatório (4)
In: TÉRREO-HID
Type - Material: Cromado - Docol
Type - Pset_ManufacturerTypeInformation - Manufacturer: Docol
Pset_DistributionFlowElementCommon - Reference: Lavatório; sets with these values: 2
Name (Sifao para lavatorio - DocolBasicos:Lavatório:...) | Group
3625024 | Esgoto Primário 2
3625943 | Esgoto Primário 2
3632400 | Esgoto Primário 3
3654927 | Esgoto Primário 16

# IfcFlowTerminal: Tampa Caixa D_Agua - Agua Fria - MEP -Tigre:Tampa - 500 L, Tampa Caixa D_Agua - Agua Fria - MEP -Tigre:Tampa - 500 L:3628162
In: TÉRREO-HID
Type - Material: PEMD Azul
Type - Pset_ManufacturerTypeInformation - Manufacturer: © Tigre S/A
Pset_DistributionFlowElementCommon - Reference: Tampa - 500 L; sets with these values: 2

# IfcFlowTerminal: Torneira Boia - Agua Fria - MEP -Tigre:1/2", Torneira Boia - Agua Fria - MEP -Tigre:1/2":3628158
In: TÉRREO-HID
Type - Material: PEMD Azul
Type - Pset_ManufacturerTypeInformation - Manufacturer: © Tigre S/A
Material: PEMD Azul, Plastic
Pset_DistributionFlowElementCommon - Reference: 1/2"; sets with these values: 2

# IfcWallStandardCase: Parede básica:Wall 1, Parede básica:Wall 1:3784195
In: TÉRREO-HID
Type - PredefinedType: STANDARD; Material: Default Wall 20 cm
Type - Pset_WallCommon - IsExternal: yes
Pset_QuantityTakeOff - Reference: Wall 1; sets with these values: 2
Pset_WallCommon - Reference: Wall 1; ExtendToStructure: no; LoadBearing: no
